VERSION 5.8 ;
BUSBITCHARS "[]" ;
DIVIDERCHAR "/" ;
UNITS
    DATABASE MICRONS 2000 ;
END UNITS

VIA gemm_compute_array_via1_2_960_340_1_3_300_300
  VIARULE Via1Array-0 ;
  CUTSIZE 0.07 0.07 ;
  LAYERS metal1 via1 metal2 ;
  CUTSPACING 0.08 0.08 ;
  ENCLOSURE 0.035 0.05 0.035 0.035 ;
  ROWCOL 1 3 ;
END gemm_compute_array_via1_2_960_340_1_3_300_300

VIA gemm_compute_array_via2_3_960_340_1_3_320_320
  VIARULE Via2Array-0 ;
  CUTSIZE 0.07 0.07 ;
  LAYERS metal2 via2 metal3 ;
  CUTSPACING 0.09 0.09 ;
  ENCLOSURE 0.035 0.035 0.035 0.035 ;
  ROWCOL 1 3 ;
END gemm_compute_array_via2_3_960_340_1_3_320_320

VIA gemm_compute_array_via3_4_960_340_1_3_320_320
  VIARULE Via3Array-0 ;
  CUTSIZE 0.07 0.07 ;
  LAYERS metal3 via3 metal4 ;
  CUTSPACING 0.09 0.09 ;
  ENCLOSURE 0.035 0.035 0.045 0.035 ;
  ROWCOL 1 3 ;
END gemm_compute_array_via3_4_960_340_1_3_320_320

VIA gemm_compute_array_via4_5_960_2800_5_2_600_600
  VIARULE Via4Array-0 ;
  CUTSIZE 0.14 0.14 ;
  LAYERS metal4 via4 metal5 ;
  CUTSPACING 0.16 0.16 ;
  ENCLOSURE 0.02 0 0 0 ;
  ROWCOL 5 2 ;
END gemm_compute_array_via4_5_960_2800_5_2_600_600

VIA gemm_compute_array_via5_6_960_2800_5_2_600_600
  VIARULE Via5Array-0 ;
  CUTSIZE 0.14 0.14 ;
  LAYERS metal5 via5 metal6 ;
  CUTSPACING 0.16 0.16 ;
  ENCLOSURE 0 0 0 0 ;
  ROWCOL 5 2 ;
END gemm_compute_array_via5_6_960_2800_5_2_600_600

VIA gemm_compute_array_via6_7_960_2800_4_1_600_600
  VIARULE Via6Array-0 ;
  CUTSIZE 0.14 0.14 ;
  LAYERS metal6 via6 metal7 ;
  CUTSPACING 0.16 0.16 ;
  ENCLOSURE 0 0 0.13 0.18 ;
  ROWCOL 4 1 ;
END gemm_compute_array_via6_7_960_2800_4_1_600_600

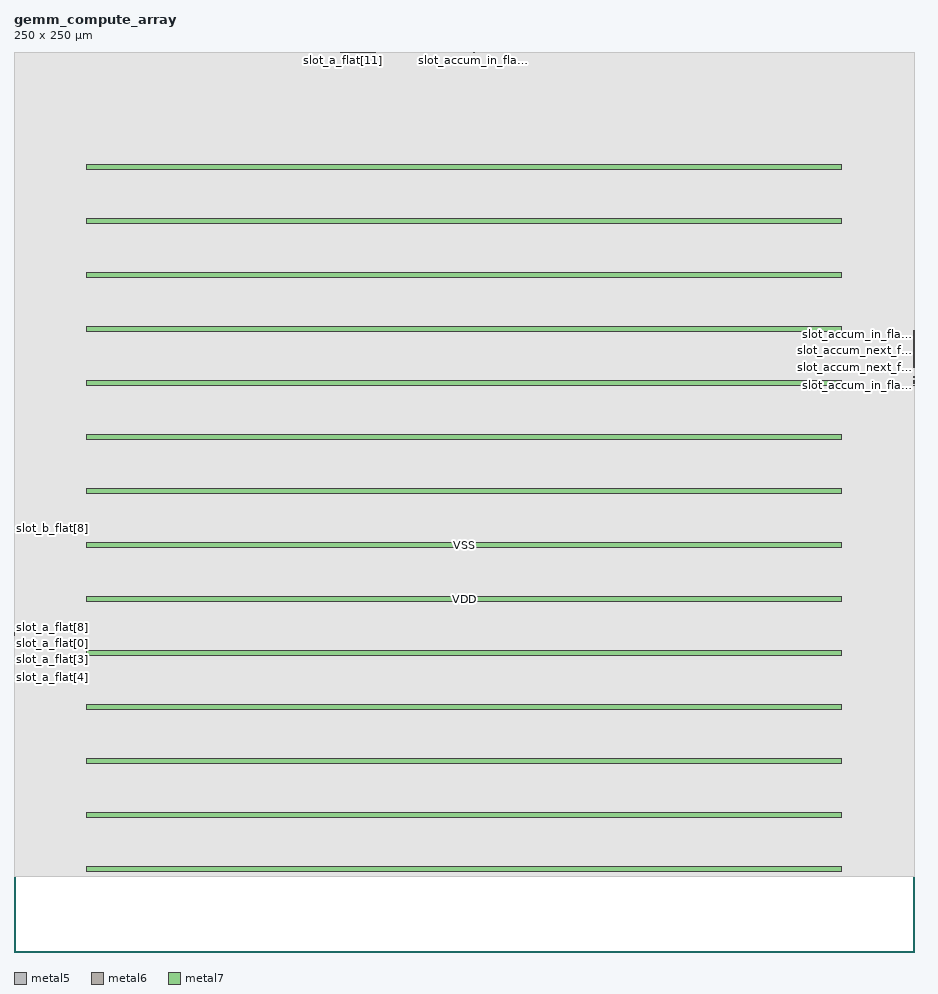
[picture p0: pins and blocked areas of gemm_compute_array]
MACRO gemm_compute_array
  FOREIGN gemm_compute_array 0 0 ;
  CLASS BLOCK ;
  SIZE 250 BY 250 ;
  PIN slot_a_flat[0]
    DIRECTION INPUT ;
    USE SIGNAL ;
    PORT
      LAYER metal5 ;
        RECT  0 85.68 0.14 85.82 ;
    END
  END slot_a_flat[0]
  PIN slot_a_flat[10]
    DIRECTION INPUT ;
    USE SIGNAL ;
    PORT
      LAYER metal6 ;
        RECT  100.265 249.86 100.405 250 ;
    END
  END slot_a_flat[10]
  PIN slot_a_flat[11]
    DIRECTION INPUT ;
    USE SIGNAL ;
    PORT
      LAYER metal6 ;
        RECT  91.305 249.86 91.445 250 ;
    END
  END slot_a_flat[11]
  PIN slot_a_flat[12]
    DIRECTION INPUT ;
    USE SIGNAL ;
    PORT
      LAYER metal6 ;
        RECT  96.905 249.86 97.045 250 ;
    END
  END slot_a_flat[12]
  PIN slot_a_flat[13]
    DIRECTION INPUT ;
    USE SIGNAL ;
    PORT
      LAYER metal6 ;
        RECT  98.585 249.86 98.725 250 ;
    END
  END slot_a_flat[13]
  PIN slot_a_flat[14]
    DIRECTION INPUT ;
    USE SIGNAL ;
    PORT
      LAYER metal6 ;
        RECT  95.225 249.86 95.365 250 ;
    END
  END slot_a_flat[14]
  PIN slot_a_flat[15]
    DIRECTION INPUT ;
    USE SIGNAL ;
    PORT
      LAYER metal5 ;
        RECT  249.86 158.48 250 158.62 ;
    END
  END slot_a_flat[15]
  PIN slot_a_flat[1]
    DIRECTION INPUT ;
    USE SIGNAL ;
    PORT
      LAYER metal5 ;
        RECT  0 85.12 0.14 85.26 ;
    END
  END slot_a_flat[1]
  PIN slot_a_flat[2]
    DIRECTION INPUT ;
    USE SIGNAL ;
    PORT
      LAYER metal5 ;
        RECT  0 84 0.14 84.14 ;
    END
  END slot_a_flat[2]
  PIN slot_a_flat[3]
    DIRECTION INPUT ;
    USE SIGNAL ;
    PORT
      LAYER metal5 ;
        RECT  0 83.44 0.14 83.58 ;
    END
  END slot_a_flat[3]
  PIN slot_a_flat[4]
    DIRECTION INPUT ;
    USE SIGNAL ;
    PORT
      LAYER metal5 ;
        RECT  0 78.4 0.14 78.54 ;
    END
  END slot_a_flat[4]
  PIN slot_a_flat[5]
    DIRECTION INPUT ;
    USE SIGNAL ;
    PORT
      LAYER metal5 ;
        RECT  0 77.84 0.14 77.98 ;
    END
  END slot_a_flat[5]
  PIN slot_a_flat[6]
    DIRECTION INPUT ;
    USE SIGNAL ;
    PORT
      LAYER metal5 ;
        RECT  0 77.28 0.14 77.42 ;
    END
  END slot_a_flat[6]
  PIN slot_a_flat[7]
    DIRECTION INPUT ;
    USE SIGNAL ;
    PORT
      LAYER metal5 ;
        RECT  0 79.52 0.14 79.66 ;
    END
  END slot_a_flat[7]
  PIN slot_a_flat[8]
    DIRECTION INPUT ;
    USE SIGNAL ;
    PORT
      LAYER metal5 ;
        RECT  0 87.92 0.14 88.06 ;
    END
  END slot_a_flat[8]
  PIN slot_a_flat[9]
    DIRECTION INPUT ;
    USE SIGNAL ;
    PORT
      LAYER metal5 ;
        RECT  0 82.88 0.14 83.02 ;
    END
  END slot_a_flat[9]
  PIN slot_accum_in_flat[0]
    DIRECTION INPUT ;
    USE SIGNAL ;
    PORT
      LAYER metal6 ;
        RECT  92.425 249.86 92.565 250 ;
    END
  END slot_accum_in_flat[0]
  PIN slot_accum_in_flat[10]
    DIRECTION INPUT ;
    USE SIGNAL ;
    PORT
      LAYER metal5 ;
        RECT  249.86 171.36 250 171.5 ;
    END
  END slot_accum_in_flat[10]
  PIN slot_accum_in_flat[11]
    DIRECTION INPUT ;
    USE SIGNAL ;
    PORT
      LAYER metal5 ;
        RECT  249.86 170.24 250 170.38 ;
    END
  END slot_accum_in_flat[11]
  PIN slot_accum_in_flat[12]
    DIRECTION INPUT ;
    USE SIGNAL ;
    PORT
      LAYER metal6 ;
        RECT  127.705 249.86 127.845 250 ;
    END
  END slot_accum_in_flat[12]
  PIN slot_accum_in_flat[13]
    DIRECTION INPUT ;
    USE SIGNAL ;
    PORT
      LAYER metal5 ;
        RECT  249.86 172.48 250 172.62 ;
    END
  END slot_accum_in_flat[13]
  PIN slot_accum_in_flat[14]
    DIRECTION INPUT ;
    USE SIGNAL ;
    PORT
      LAYER metal5 ;
        RECT  249.86 171.92 250 172.06 ;
    END
  END slot_accum_in_flat[14]
  PIN slot_accum_in_flat[15]
    DIRECTION INPUT ;
    USE SIGNAL ;
    PORT
      LAYER metal5 ;
        RECT  249.86 157.36 250 157.5 ;
    END
  END slot_accum_in_flat[15]
  PIN slot_accum_in_flat[1]
    DIRECTION INPUT ;
    USE SIGNAL ;
    PORT
      LAYER metal6 ;
        RECT  97.465 249.86 97.605 250 ;
    END
  END slot_accum_in_flat[1]
  PIN slot_accum_in_flat[2]
    DIRECTION INPUT ;
    USE SIGNAL ;
    PORT
      LAYER metal6 ;
        RECT  99.705 249.86 99.845 250 ;
    END
  END slot_accum_in_flat[2]
  PIN slot_accum_in_flat[3]
    DIRECTION INPUT ;
    USE SIGNAL ;
    PORT
      LAYER metal6 ;
        RECT  94.665 249.86 94.805 250 ;
    END
  END slot_accum_in_flat[3]
  PIN slot_accum_in_flat[4]
    DIRECTION INPUT ;
    USE SIGNAL ;
    PORT
      LAYER metal6 ;
        RECT  93.545 249.86 93.685 250 ;
    END
  END slot_accum_in_flat[4]
  PIN slot_accum_in_flat[5]
    DIRECTION INPUT ;
    USE SIGNAL ;
    PORT
      LAYER metal6 ;
        RECT  94.105 249.86 94.245 250 ;
    END
  END slot_accum_in_flat[5]
  PIN slot_accum_in_flat[6]
    DIRECTION INPUT ;
    USE SIGNAL ;
    PORT
      LAYER metal6 ;
        RECT  91.865 249.86 92.005 250 ;
    END
  END slot_accum_in_flat[6]
  PIN slot_accum_in_flat[7]
    DIRECTION INPUT ;
    USE SIGNAL ;
    PORT
      LAYER metal6 ;
        RECT  92.985 249.86 93.125 250 ;
    END
  END slot_accum_in_flat[7]
  PIN slot_accum_in_flat[8]
    DIRECTION INPUT ;
    USE SIGNAL ;
    PORT
      LAYER metal6 ;
        RECT  109.225 249.86 109.365 250 ;
    END
  END slot_accum_in_flat[8]
  PIN slot_accum_in_flat[9]
    DIRECTION INPUT ;
    USE SIGNAL ;
    PORT
      LAYER metal6 ;
        RECT  105.865 249.86 106.005 250 ;
    END
  END slot_accum_in_flat[9]
  PIN slot_accum_next_flat[0]
    DIRECTION OUTPUT ;
    USE SIGNAL ;
    PORT
      LAYER metal5 ;
        RECT  249.86 162.4 250 162.54 ;
    END
  END slot_accum_next_flat[0]
  PIN slot_accum_next_flat[10]
    DIRECTION OUTPUT ;
    USE SIGNAL ;
    PORT
      LAYER metal5 ;
        RECT  249.86 164.08 250 164.22 ;
    END
  END slot_accum_next_flat[10]
  PIN slot_accum_next_flat[11]
    DIRECTION OUTPUT ;
    USE SIGNAL ;
    PORT
      LAYER metal5 ;
        RECT  249.86 164.64 250 164.78 ;
    END
  END slot_accum_next_flat[11]
  PIN slot_accum_next_flat[12]
    DIRECTION OUTPUT ;
    USE SIGNAL ;
    PORT
      LAYER metal5 ;
        RECT  249.86 169.12 250 169.26 ;
    END
  END slot_accum_next_flat[12]
  PIN slot_accum_next_flat[13]
    DIRECTION OUTPUT ;
    USE SIGNAL ;
    PORT
      LAYER metal5 ;
        RECT  249.86 168.56 250 168.7 ;
    END
  END slot_accum_next_flat[13]
  PIN slot_accum_next_flat[14]
    DIRECTION OUTPUT ;
    USE SIGNAL ;
    PORT
      LAYER metal5 ;
        RECT  249.86 165.76 250 165.9 ;
    END
  END slot_accum_next_flat[14]
  PIN slot_accum_next_flat[15]
    DIRECTION OUTPUT ;
    USE SIGNAL ;
    PORT
      LAYER metal5 ;
        RECT  249.86 159.6 250 159.74 ;
    END
  END slot_accum_next_flat[15]
  PIN slot_accum_next_flat[1]
    DIRECTION OUTPUT ;
    USE SIGNAL ;
    PORT
      LAYER metal5 ;
        RECT  249.86 166.32 250 166.46 ;
    END
  END slot_accum_next_flat[1]
  PIN slot_accum_next_flat[2]
    DIRECTION OUTPUT ;
    USE SIGNAL ;
    PORT
      LAYER metal5 ;
        RECT  249.86 166.88 250 167.02 ;
    END
  END slot_accum_next_flat[2]
  PIN slot_accum_next_flat[3]
    DIRECTION OUTPUT ;
    USE SIGNAL ;
    PORT
      LAYER metal5 ;
        RECT  249.86 170.8 250 170.94 ;
    END
  END slot_accum_next_flat[3]
  PIN slot_accum_next_flat[4]
    DIRECTION OUTPUT ;
    USE SIGNAL ;
    PORT
      LAYER metal5 ;
        RECT  249.86 168 250 168.14 ;
    END
  END slot_accum_next_flat[4]
  PIN slot_accum_next_flat[5]
    DIRECTION OUTPUT ;
    USE SIGNAL ;
    PORT
      LAYER metal5 ;
        RECT  249.86 165.2 250 165.34 ;
    END
  END slot_accum_next_flat[5]
  PIN slot_accum_next_flat[6]
    DIRECTION OUTPUT ;
    USE SIGNAL ;
    PORT
      LAYER metal5 ;
        RECT  249.86 163.52 250 163.66 ;
    END
  END slot_accum_next_flat[6]
  PIN slot_accum_next_flat[7]
    DIRECTION OUTPUT ;
    USE SIGNAL ;
    PORT
      LAYER metal5 ;
        RECT  249.86 162.96 250 163.1 ;
    END
  END slot_accum_next_flat[7]
  PIN slot_accum_next_flat[8]
    DIRECTION OUTPUT ;
    USE SIGNAL ;
    PORT
      LAYER metal5 ;
        RECT  249.86 167.44 250 167.58 ;
    END
  END slot_accum_next_flat[8]
  PIN slot_accum_next_flat[9]
    DIRECTION OUTPUT ;
    USE SIGNAL ;
    PORT
      LAYER metal5 ;
        RECT  249.86 169.68 250 169.82 ;
    END
  END slot_accum_next_flat[9]
  PIN slot_b_flat[0]
    DIRECTION INPUT ;
    USE SIGNAL ;
    PORT
      LAYER metal5 ;
        RECT  0 86.8 0.14 86.94 ;
    END
  END slot_b_flat[0]
  PIN slot_b_flat[10]
    DIRECTION INPUT ;
    USE SIGNAL ;
    PORT
      LAYER metal6 ;
        RECT  99.145 249.86 99.285 250 ;
    END
  END slot_b_flat[10]
  PIN slot_b_flat[11]
    DIRECTION INPUT ;
    USE SIGNAL ;
    PORT
      LAYER metal6 ;
        RECT  90.745 249.86 90.885 250 ;
    END
  END slot_b_flat[11]
  PIN slot_b_flat[12]
    DIRECTION INPUT ;
    USE SIGNAL ;
    PORT
      LAYER metal6 ;
        RECT  96.345 249.86 96.485 250 ;
    END
  END slot_b_flat[12]
  PIN slot_b_flat[13]
    DIRECTION INPUT ;
    USE SIGNAL ;
    PORT
      LAYER metal6 ;
        RECT  98.025 249.86 98.165 250 ;
    END
  END slot_b_flat[13]
  PIN slot_b_flat[14]
    DIRECTION INPUT ;
    USE SIGNAL ;
    PORT
      LAYER metal6 ;
        RECT  95.785 249.86 95.925 250 ;
    END
  END slot_b_flat[14]
  PIN slot_b_flat[15]
    DIRECTION INPUT ;
    USE SIGNAL ;
    PORT
      LAYER metal5 ;
        RECT  249.86 157.92 250 158.06 ;
    END
  END slot_b_flat[15]
  PIN slot_b_flat[1]
    DIRECTION INPUT ;
    USE SIGNAL ;
    PORT
      LAYER metal5 ;
        RECT  0 86.24 0.14 86.38 ;
    END
  END slot_b_flat[1]
  PIN slot_b_flat[2]
    DIRECTION INPUT ;
    USE SIGNAL ;
    PORT
      LAYER metal5 ;
        RECT  0 84.56 0.14 84.7 ;
    END
  END slot_b_flat[2]
  PIN slot_b_flat[3]
    DIRECTION INPUT ;
    USE SIGNAL ;
    PORT
      LAYER metal5 ;
        RECT  0 87.36 0.14 87.5 ;
    END
  END slot_b_flat[3]
  PIN slot_b_flat[4]
    DIRECTION INPUT ;
    USE SIGNAL ;
    PORT
      LAYER metal5 ;
        RECT  0 80.64 0.14 80.78 ;
    END
  END slot_b_flat[4]
  PIN slot_b_flat[5]
    DIRECTION INPUT ;
    USE SIGNAL ;
    PORT
      LAYER metal5 ;
        RECT  0 80.08 0.14 80.22 ;
    END
  END slot_b_flat[5]
  PIN slot_b_flat[6]
    DIRECTION INPUT ;
    USE SIGNAL ;
    PORT
      LAYER metal5 ;
        RECT  0 81.2 0.14 81.34 ;
    END
  END slot_b_flat[6]
  PIN slot_b_flat[7]
    DIRECTION INPUT ;
    USE SIGNAL ;
    PORT
      LAYER metal5 ;
        RECT  0 81.76 0.14 81.9 ;
    END
  END slot_b_flat[7]
  PIN slot_b_flat[8]
    DIRECTION INPUT ;
    USE SIGNAL ;
    PORT
      LAYER metal5 ;
        RECT  0 117.6 0.14 117.74 ;
    END
  END slot_b_flat[8]
  PIN slot_b_flat[9]
    DIRECTION INPUT ;
    USE SIGNAL ;
    PORT
      LAYER metal5 ;
        RECT  0 88.48 0.14 88.62 ;
    END
  END slot_b_flat[9]
  PIN VSS
    DIRECTION INOUT ;
    USE GROUND ;
    PORT
      LAYER metal7 ;
        RECT  20.14 202.3 229.9 203.7 ;
        RECT  20.14 172.3 229.9 173.7 ;
        RECT  20.14 142.3 229.9 143.7 ;
        RECT  20.14 112.3 229.9 113.7 ;
        RECT  20.14 82.3 229.9 83.7 ;
        RECT  20.14 52.3 229.9 53.7 ;
        RECT  20.14 22.3 229.9 23.7 ;
    END
  END VSS
  PIN VDD
    DIRECTION INOUT ;
    USE POWER ;
    PORT
      LAYER metal7 ;
        RECT  20.14 217.3 229.9 218.7 ;
        RECT  20.14 187.3 229.9 188.7 ;
        RECT  20.14 157.3 229.9 158.7 ;
        RECT  20.14 127.3 229.9 128.7 ;
        RECT  20.14 97.3 229.9 98.7 ;
        RECT  20.14 67.3 229.9 68.7 ;
        RECT  20.14 37.3 229.9 38.7 ;
    END
  END VDD
  OBS
    LAYER metal1 ;
     RECT  0 20.915 250 250 ;
    LAYER metal2 ;
     RECT  0 20.915 250 250 ;
    LAYER metal3 ;
     RECT  0 20.915 250 250 ;
    LAYER metal4 ;
     RECT  0 20.915 250 250 ;
    LAYER metal5 ;
     RECT  0 20.915 250 250 ;
    LAYER metal6 ;
     RECT  0 20.915 250 250 ;
    LAYER metal7 ;
     RECT  0 20.915 250 250 ;
    LAYER metal8 ;
     RECT  0 20.915 250 250 ;
    LAYER metal9 ;
     RECT  0 20.915 250 250 ;
  END
END gemm_compute_array
END LIBRARY
